VERSION 5.7 ;
  NOWIREEXTENSIONATPIN ON ;
  DIVIDERCHAR "/" ;
  BUSBITCHARS "[]" ;
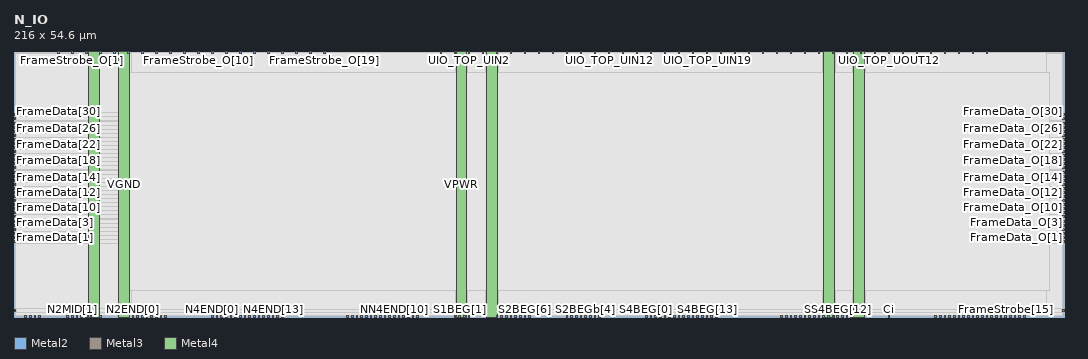
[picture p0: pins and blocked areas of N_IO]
MACRO N_IO
  CLASS BLOCK ;
  FOREIGN N_IO ;
  ORIGIN 0.000 0.000 ;
  SIZE 216.000 BY 54.600 ;
  PIN Ci
    DIRECTION INPUT ;
    USE SIGNAL ;
    PORT
      LAYER Metal2 ;
        RECT 179.800 0.000 180.200 0.400 ;
    END
  END Ci
  PIN FrameData[0]
    DIRECTION INPUT ;
    USE SIGNAL ;
    ANTENNAGATEAREA 0.180700 ;
    ANTENNADIFFAREA 2.015400 ;
    PORT
      LAYER Metal3 ;
        RECT 0.000 15.340 0.400 15.740 ;
    END
  END FrameData[0]
  PIN FrameData[10]
    DIRECTION INPUT ;
    USE SIGNAL ;
    ANTENNAGATEAREA 0.180700 ;
    ANTENNADIFFAREA 2.015400 ;
    PORT
      LAYER Metal3 ;
        RECT 0.000 23.740 0.400 24.140 ;
    END
  END FrameData[10]
  PIN FrameData[11]
    DIRECTION INPUT ;
    USE SIGNAL ;
    ANTENNAGATEAREA 0.180700 ;
    ANTENNADIFFAREA 2.015400 ;
    PORT
      LAYER Metal3 ;
        RECT 0.000 24.580 0.400 24.980 ;
    END
  END FrameData[11]
  PIN FrameData[12]
    DIRECTION INPUT ;
    USE SIGNAL ;
    ANTENNAGATEAREA 0.180700 ;
    ANTENNADIFFAREA 2.015400 ;
    PORT
      LAYER Metal3 ;
        RECT 0.000 25.420 0.400 25.820 ;
    END
  END FrameData[12]
  PIN FrameData[13]
    DIRECTION INPUT ;
    USE SIGNAL ;
    ANTENNAGATEAREA 0.180700 ;
    ANTENNADIFFAREA 2.015400 ;
    PORT
      LAYER Metal3 ;
        RECT 0.000 26.260 0.400 26.660 ;
    END
  END FrameData[13]
  PIN FrameData[14]
    DIRECTION INPUT ;
    USE SIGNAL ;
    ANTENNAGATEAREA 0.180700 ;
    ANTENNADIFFAREA 2.015400 ;
    PORT
      LAYER Metal3 ;
        RECT 0.000 27.100 0.400 27.500 ;
    END
  END FrameData[14]
  PIN FrameData[15]
    DIRECTION INPUT ;
    USE SIGNAL ;
    ANTENNAGATEAREA 0.180700 ;
    ANTENNADIFFAREA 2.015400 ;
    PORT
      LAYER Metal3 ;
        RECT 0.000 27.940 0.400 28.340 ;
    END
  END FrameData[15]
  PIN FrameData[16]
    DIRECTION INPUT ;
    USE SIGNAL ;
    ANTENNAGATEAREA 0.180700 ;
    ANTENNADIFFAREA 2.015400 ;
    PORT
      LAYER Metal3 ;
        RECT 0.000 28.780 0.400 29.180 ;
    END
  END FrameData[16]
  PIN FrameData[17]
    DIRECTION INPUT ;
    USE SIGNAL ;
    ANTENNAGATEAREA 0.180700 ;
    ANTENNADIFFAREA 2.015400 ;
    PORT
      LAYER Metal3 ;
        RECT 0.000 29.620 0.400 30.020 ;
    END
  END FrameData[17]
  PIN FrameData[18]
    DIRECTION INPUT ;
    USE SIGNAL ;
    ANTENNAGATEAREA 0.180700 ;
    ANTENNADIFFAREA 2.015400 ;
    PORT
      LAYER Metal3 ;
        RECT 0.000 30.460 0.400 30.860 ;
    END
  END FrameData[18]
  PIN FrameData[19]
    DIRECTION INPUT ;
    USE SIGNAL ;
    ANTENNAGATEAREA 0.180700 ;
    ANTENNADIFFAREA 2.015400 ;
    PORT
      LAYER Metal3 ;
        RECT 0.000 31.300 0.400 31.700 ;
    END
  END FrameData[19]
  PIN FrameData[1]
    DIRECTION INPUT ;
    USE SIGNAL ;
    ANTENNAGATEAREA 0.180700 ;
    ANTENNADIFFAREA 2.015400 ;
    PORT
      LAYER Metal3 ;
        RECT 0.000 16.180 0.400 16.580 ;
    END
  END FrameData[1]
  PIN FrameData[20]
    DIRECTION INPUT ;
    USE SIGNAL ;
    ANTENNAGATEAREA 0.180700 ;
    ANTENNADIFFAREA 2.015400 ;
    PORT
      LAYER Metal3 ;
        RECT 0.000 32.140 0.400 32.540 ;
    END
  END FrameData[20]
  PIN FrameData[21]
    DIRECTION INPUT ;
    USE SIGNAL ;
    ANTENNAGATEAREA 0.180700 ;
    ANTENNADIFFAREA 2.015400 ;
    PORT
      LAYER Metal3 ;
        RECT 0.000 32.980 0.400 33.380 ;
    END
  END FrameData[21]
  PIN FrameData[22]
    DIRECTION INPUT ;
    USE SIGNAL ;
    ANTENNAGATEAREA 0.180700 ;
    ANTENNADIFFAREA 2.015400 ;
    PORT
      LAYER Metal3 ;
        RECT 0.000 33.820 0.400 34.220 ;
    END
  END FrameData[22]
  PIN FrameData[23]
    DIRECTION INPUT ;
    USE SIGNAL ;
    ANTENNAGATEAREA 0.180700 ;
    ANTENNADIFFAREA 2.015400 ;
    PORT
      LAYER Metal3 ;
        RECT 0.000 34.660 0.400 35.060 ;
    END
  END FrameData[23]
  PIN FrameData[24]
    DIRECTION INPUT ;
    USE SIGNAL ;
    ANTENNAGATEAREA 0.180700 ;
    ANTENNADIFFAREA 2.015400 ;
    PORT
      LAYER Metal3 ;
        RECT 0.000 35.500 0.400 35.900 ;
    END
  END FrameData[24]
  PIN FrameData[25]
    DIRECTION INPUT ;
    USE SIGNAL ;
    ANTENNAGATEAREA 0.180700 ;
    ANTENNADIFFAREA 2.015400 ;
    PORT
      LAYER Metal3 ;
        RECT 0.000 36.340 0.400 36.740 ;
    END
  END FrameData[25]
  PIN FrameData[26]
    DIRECTION INPUT ;
    USE SIGNAL ;
    ANTENNAGATEAREA 0.180700 ;
    ANTENNADIFFAREA 2.015400 ;
    PORT
      LAYER Metal3 ;
        RECT 0.000 37.180 0.400 37.580 ;
    END
  END FrameData[26]
  PIN FrameData[27]
    DIRECTION INPUT ;
    USE SIGNAL ;
    ANTENNAGATEAREA 0.180700 ;
    ANTENNADIFFAREA 2.015400 ;
    PORT
      LAYER Metal3 ;
        RECT 0.000 38.020 0.400 38.420 ;
    END
  END FrameData[27]
  PIN FrameData[28]
    DIRECTION INPUT ;
    USE SIGNAL ;
    ANTENNAGATEAREA 0.180700 ;
    ANTENNADIFFAREA 2.015400 ;
    PORT
      LAYER Metal3 ;
        RECT 0.000 38.860 0.400 39.260 ;
    END
  END FrameData[28]
  PIN FrameData[29]
    DIRECTION INPUT ;
    USE SIGNAL ;
    ANTENNAGATEAREA 0.180700 ;
    ANTENNADIFFAREA 2.015400 ;
    PORT
      LAYER Metal3 ;
        RECT 0.000 39.700 0.400 40.100 ;
    END
  END FrameData[29]
  PIN FrameData[2]
    DIRECTION INPUT ;
    USE SIGNAL ;
    ANTENNAGATEAREA 0.180700 ;
    ANTENNADIFFAREA 2.015400 ;
    PORT
      LAYER Metal3 ;
        RECT 0.000 17.020 0.400 17.420 ;
    END
  END FrameData[2]
  PIN FrameData[30]
    DIRECTION INPUT ;
    USE SIGNAL ;
    ANTENNAGATEAREA 0.180700 ;
    ANTENNADIFFAREA 2.015400 ;
    PORT
      LAYER Metal3 ;
        RECT 0.000 40.540 0.400 40.940 ;
    END
  END FrameData[30]
  PIN FrameData[31]
    DIRECTION INPUT ;
    USE SIGNAL ;
    ANTENNAGATEAREA 0.180700 ;
    ANTENNADIFFAREA 2.015400 ;
    PORT
      LAYER Metal3 ;
        RECT 0.000 41.380 0.400 41.780 ;
    END
  END FrameData[31]
  PIN FrameData[3]
    DIRECTION INPUT ;
    USE SIGNAL ;
    ANTENNAGATEAREA 0.180700 ;
    ANTENNADIFFAREA 2.015400 ;
    PORT
      LAYER Metal3 ;
        RECT 0.000 17.860 0.400 18.260 ;
    END
  END FrameData[3]
  PIN FrameData[4]
    DIRECTION INPUT ;
    USE SIGNAL ;
    ANTENNAGATEAREA 0.180700 ;
    ANTENNADIFFAREA 2.015400 ;
    PORT
      LAYER Metal3 ;
        RECT 0.000 18.700 0.400 19.100 ;
    END
  END FrameData[4]
  PIN FrameData[5]
    DIRECTION INPUT ;
    USE SIGNAL ;
    ANTENNAGATEAREA 0.180700 ;
    ANTENNADIFFAREA 2.015400 ;
    PORT
      LAYER Metal3 ;
        RECT 0.000 19.540 0.400 19.940 ;
    END
  END FrameData[5]
  PIN FrameData[6]
    DIRECTION INPUT ;
    USE SIGNAL ;
    ANTENNAGATEAREA 0.180700 ;
    ANTENNADIFFAREA 2.015400 ;
    PORT
      LAYER Metal3 ;
        RECT 0.000 20.380 0.400 20.780 ;
    END
  END FrameData[6]
  PIN FrameData[7]
    DIRECTION INPUT ;
    USE SIGNAL ;
    ANTENNAGATEAREA 0.180700 ;
    ANTENNADIFFAREA 2.015400 ;
    PORT
      LAYER Metal3 ;
        RECT 0.000 21.220 0.400 21.620 ;
    END
  END FrameData[7]
  PIN FrameData[8]
    DIRECTION INPUT ;
    USE SIGNAL ;
    ANTENNAGATEAREA 0.180700 ;
    ANTENNADIFFAREA 2.015400 ;
    PORT
      LAYER Metal3 ;
        RECT 0.000 22.060 0.400 22.460 ;
    END
  END FrameData[8]
  PIN FrameData[9]
    DIRECTION INPUT ;
    USE SIGNAL ;
    ANTENNAGATEAREA 0.180700 ;
    ANTENNADIFFAREA 2.015400 ;
    PORT
      LAYER Metal3 ;
        RECT 0.000 22.900 0.400 23.300 ;
    END
  END FrameData[9]
  PIN FrameData_O[0]
    DIRECTION OUTPUT ;
    USE SIGNAL ;
    ANTENNADIFFAREA 2.724000 ;
    PORT
      LAYER Metal3 ;
        RECT 215.600 15.340 216.000 15.740 ;
    END
  END FrameData_O[0]
  PIN FrameData_O[10]
    DIRECTION OUTPUT ;
    USE SIGNAL ;
    ANTENNADIFFAREA 2.724000 ;
    PORT
      LAYER Metal3 ;
        RECT 215.600 23.740 216.000 24.140 ;
    END
  END FrameData_O[10]
  PIN FrameData_O[11]
    DIRECTION OUTPUT ;
    USE SIGNAL ;
    ANTENNADIFFAREA 2.724000 ;
    PORT
      LAYER Metal3 ;
        RECT 215.600 24.580 216.000 24.980 ;
    END
  END FrameData_O[11]
  PIN FrameData_O[12]
    DIRECTION OUTPUT ;
    USE SIGNAL ;
    ANTENNADIFFAREA 2.724000 ;
    PORT
      LAYER Metal3 ;
        RECT 215.600 25.420 216.000 25.820 ;
    END
  END FrameData_O[12]
  PIN FrameData_O[13]
    DIRECTION OUTPUT ;
    USE SIGNAL ;
    ANTENNADIFFAREA 2.724000 ;
    PORT
      LAYER Metal3 ;
        RECT 215.600 26.260 216.000 26.660 ;
    END
  END FrameData_O[13]
  PIN FrameData_O[14]
    DIRECTION OUTPUT ;
    USE SIGNAL ;
    ANTENNADIFFAREA 2.724000 ;
    PORT
      LAYER Metal3 ;
        RECT 215.600 27.100 216.000 27.500 ;
    END
  END FrameData_O[14]
  PIN FrameData_O[15]
    DIRECTION OUTPUT ;
    USE SIGNAL ;
    ANTENNADIFFAREA 2.724000 ;
    PORT
      LAYER Metal3 ;
        RECT 215.600 27.940 216.000 28.340 ;
    END
  END FrameData_O[15]
  PIN FrameData_O[16]
    DIRECTION OUTPUT ;
    USE SIGNAL ;
    ANTENNADIFFAREA 2.724000 ;
    PORT
      LAYER Metal3 ;
        RECT 215.600 28.780 216.000 29.180 ;
    END
  END FrameData_O[16]
  PIN FrameData_O[17]
    DIRECTION OUTPUT ;
    USE SIGNAL ;
    ANTENNADIFFAREA 2.724000 ;
    PORT
      LAYER Metal3 ;
        RECT 215.600 29.620 216.000 30.020 ;
    END
  END FrameData_O[17]
  PIN FrameData_O[18]
    DIRECTION OUTPUT ;
    USE SIGNAL ;
    ANTENNADIFFAREA 2.724000 ;
    PORT
      LAYER Metal3 ;
        RECT 215.600 30.460 216.000 30.860 ;
    END
  END FrameData_O[18]
  PIN FrameData_O[19]
    DIRECTION OUTPUT ;
    USE SIGNAL ;
    ANTENNADIFFAREA 2.724000 ;
    PORT
      LAYER Metal3 ;
        RECT 215.600 31.300 216.000 31.700 ;
    END
  END FrameData_O[19]
  PIN FrameData_O[1]
    DIRECTION OUTPUT ;
    USE SIGNAL ;
    ANTENNADIFFAREA 2.724000 ;
    PORT
      LAYER Metal3 ;
        RECT 215.600 16.180 216.000 16.580 ;
    END
  END FrameData_O[1]
  PIN FrameData_O[20]
    DIRECTION OUTPUT ;
    USE SIGNAL ;
    ANTENNADIFFAREA 2.724000 ;
    PORT
      LAYER Metal3 ;
        RECT 215.600 32.140 216.000 32.540 ;
    END
  END FrameData_O[20]
  PIN FrameData_O[21]
    DIRECTION OUTPUT ;
    USE SIGNAL ;
    ANTENNADIFFAREA 2.724000 ;
    PORT
      LAYER Metal3 ;
        RECT 215.600 32.980 216.000 33.380 ;
    END
  END FrameData_O[21]
  PIN FrameData_O[22]
    DIRECTION OUTPUT ;
    USE SIGNAL ;
    ANTENNADIFFAREA 2.724000 ;
    PORT
      LAYER Metal3 ;
        RECT 215.600 33.820 216.000 34.220 ;
    END
  END FrameData_O[22]
  PIN FrameData_O[23]
    DIRECTION OUTPUT ;
    USE SIGNAL ;
    ANTENNADIFFAREA 2.724000 ;
    PORT
      LAYER Metal3 ;
        RECT 215.600 34.660 216.000 35.060 ;
    END
  END FrameData_O[23]
  PIN FrameData_O[24]
    DIRECTION OUTPUT ;
    USE SIGNAL ;
    ANTENNADIFFAREA 2.724000 ;
    PORT
      LAYER Metal3 ;
        RECT 215.600 35.500 216.000 35.900 ;
    END
  END FrameData_O[24]
  PIN FrameData_O[25]
    DIRECTION OUTPUT ;
    USE SIGNAL ;
    ANTENNADIFFAREA 2.724000 ;
    PORT
      LAYER Metal3 ;
        RECT 215.600 36.340 216.000 36.740 ;
    END
  END FrameData_O[25]
  PIN FrameData_O[26]
    DIRECTION OUTPUT ;
    USE SIGNAL ;
    ANTENNADIFFAREA 2.724000 ;
    PORT
      LAYER Metal3 ;
        RECT 215.600 37.180 216.000 37.580 ;
    END
  END FrameData_O[26]
  PIN FrameData_O[27]
    DIRECTION OUTPUT ;
    USE SIGNAL ;
    ANTENNADIFFAREA 2.724000 ;
    PORT
      LAYER Metal3 ;
        RECT 215.600 38.020 216.000 38.420 ;
    END
  END FrameData_O[27]
  PIN FrameData_O[28]
    DIRECTION OUTPUT ;
    USE SIGNAL ;
    ANTENNADIFFAREA 2.724000 ;
    PORT
      LAYER Metal3 ;
        RECT 215.600 38.860 216.000 39.260 ;
    END
  END FrameData_O[28]
  PIN FrameData_O[29]
    DIRECTION OUTPUT ;
    USE SIGNAL ;
    ANTENNADIFFAREA 2.724000 ;
    PORT
      LAYER Metal3 ;
        RECT 215.600 39.700 216.000 40.100 ;
    END
  END FrameData_O[29]
  PIN FrameData_O[2]
    DIRECTION OUTPUT ;
    USE SIGNAL ;
    ANTENNADIFFAREA 2.724000 ;
    PORT
      LAYER Metal3 ;
        RECT 215.600 17.020 216.000 17.420 ;
    END
  END FrameData_O[2]
  PIN FrameData_O[30]
    DIRECTION OUTPUT ;
    USE SIGNAL ;
    ANTENNADIFFAREA 2.724000 ;
    PORT
      LAYER Metal3 ;
        RECT 215.600 40.540 216.000 40.940 ;
    END
  END FrameData_O[30]
  PIN FrameData_O[31]
    DIRECTION OUTPUT ;
    USE SIGNAL ;
    ANTENNADIFFAREA 2.724000 ;
    PORT
      LAYER Metal3 ;
        RECT 215.600 41.380 216.000 41.780 ;
    END
  END FrameData_O[31]
  PIN FrameData_O[3]
    DIRECTION OUTPUT ;
    USE SIGNAL ;
    ANTENNADIFFAREA 2.724000 ;
    PORT
      LAYER Metal3 ;
        RECT 215.600 17.860 216.000 18.260 ;
    END
  END FrameData_O[3]
  PIN FrameData_O[4]
    DIRECTION OUTPUT ;
    USE SIGNAL ;
    ANTENNADIFFAREA 2.724000 ;
    PORT
      LAYER Metal3 ;
        RECT 215.600 18.700 216.000 19.100 ;
    END
  END FrameData_O[4]
  PIN FrameData_O[5]
    DIRECTION OUTPUT ;
    USE SIGNAL ;
    ANTENNADIFFAREA 2.724000 ;
    PORT
      LAYER Metal3 ;
        RECT 215.600 19.540 216.000 19.940 ;
    END
  END FrameData_O[5]
  PIN FrameData_O[6]
    DIRECTION OUTPUT ;
    USE SIGNAL ;
    ANTENNADIFFAREA 2.724000 ;
    PORT
      LAYER Metal3 ;
        RECT 215.600 20.380 216.000 20.780 ;
    END
  END FrameData_O[6]
  PIN FrameData_O[7]
    DIRECTION OUTPUT ;
    USE SIGNAL ;
    ANTENNADIFFAREA 2.724000 ;
    PORT
      LAYER Metal3 ;
        RECT 215.600 21.220 216.000 21.620 ;
    END
  END FrameData_O[7]
  PIN FrameData_O[8]
    DIRECTION OUTPUT ;
    USE SIGNAL ;
    ANTENNADIFFAREA 2.724000 ;
    PORT
      LAYER Metal3 ;
        RECT 215.600 22.060 216.000 22.460 ;
    END
  END FrameData_O[8]
  PIN FrameData_O[9]
    DIRECTION OUTPUT ;
    USE SIGNAL ;
    ANTENNADIFFAREA 2.724000 ;
    PORT
      LAYER Metal3 ;
        RECT 215.600 22.900 216.000 23.300 ;
    END
  END FrameData_O[9]
  PIN FrameStrobe[0]
    DIRECTION INPUT ;
    USE SIGNAL ;
    ANTENNAGATEAREA 0.180700 ;
    ANTENNADIFFAREA 2.015400 ;
    PORT
      LAYER Metal2 ;
        RECT 189.400 0.000 189.800 0.400 ;
    END
  END FrameStrobe[0]
  PIN FrameStrobe[10]
    DIRECTION INPUT ;
    USE SIGNAL ;
    ANTENNAGATEAREA 0.180700 ;
    ANTENNADIFFAREA 2.015400 ;
    PORT
      LAYER Metal2 ;
        RECT 199.000 0.000 199.400 0.400 ;
    END
  END FrameStrobe[10]
  PIN FrameStrobe[11]
    DIRECTION INPUT ;
    USE SIGNAL ;
    ANTENNAGATEAREA 0.180700 ;
    ANTENNADIFFAREA 2.015400 ;
    PORT
      LAYER Metal2 ;
        RECT 199.960 0.000 200.360 0.400 ;
    END
  END FrameStrobe[11]
  PIN FrameStrobe[12]
    DIRECTION INPUT ;
    USE SIGNAL ;
    ANTENNAGATEAREA 0.180700 ;
    ANTENNADIFFAREA 2.015400 ;
    PORT
      LAYER Metal2 ;
        RECT 200.920 0.000 201.320 0.400 ;
    END
  END FrameStrobe[12]
  PIN FrameStrobe[13]
    DIRECTION INPUT ;
    USE SIGNAL ;
    ANTENNAGATEAREA 0.180700 ;
    ANTENNADIFFAREA 2.015400 ;
    PORT
      LAYER Metal2 ;
        RECT 201.880 0.000 202.280 0.400 ;
    END
  END FrameStrobe[13]
  PIN FrameStrobe[14]
    DIRECTION INPUT ;
    USE SIGNAL ;
    ANTENNAGATEAREA 0.180700 ;
    ANTENNADIFFAREA 2.015400 ;
    PORT
      LAYER Metal2 ;
        RECT 202.840 0.000 203.240 0.400 ;
    END
  END FrameStrobe[14]
  PIN FrameStrobe[15]
    DIRECTION INPUT ;
    USE SIGNAL ;
    ANTENNAGATEAREA 0.180700 ;
    ANTENNADIFFAREA 2.015400 ;
    PORT
      LAYER Metal2 ;
        RECT 203.800 0.000 204.200 0.400 ;
    END
  END FrameStrobe[15]
  PIN FrameStrobe[16]
    DIRECTION INPUT ;
    USE SIGNAL ;
    ANTENNAGATEAREA 0.180700 ;
    ANTENNADIFFAREA 2.015400 ;
    PORT
      LAYER Metal2 ;
        RECT 204.760 0.000 205.160 0.400 ;
    END
  END FrameStrobe[16]
  PIN FrameStrobe[17]
    DIRECTION INPUT ;
    USE SIGNAL ;
    ANTENNAGATEAREA 0.180700 ;
    ANTENNADIFFAREA 2.015400 ;
    PORT
      LAYER Metal2 ;
        RECT 205.720 0.000 206.120 0.400 ;
    END
  END FrameStrobe[17]
  PIN FrameStrobe[18]
    DIRECTION INPUT ;
    USE SIGNAL ;
    ANTENNAGATEAREA 0.180700 ;
    ANTENNADIFFAREA 2.015400 ;
    PORT
      LAYER Metal2 ;
        RECT 206.680 0.000 207.080 0.400 ;
    END
  END FrameStrobe[18]
  PIN FrameStrobe[19]
    DIRECTION INPUT ;
    USE SIGNAL ;
    ANTENNAGATEAREA 0.180700 ;
    ANTENNADIFFAREA 2.015400 ;
    PORT
      LAYER Metal2 ;
        RECT 207.640 0.000 208.040 0.400 ;
    END
  END FrameStrobe[19]
  PIN FrameStrobe[1]
    DIRECTION INPUT ;
    USE SIGNAL ;
    ANTENNAGATEAREA 0.180700 ;
    ANTENNADIFFAREA 2.015400 ;
    PORT
      LAYER Metal2 ;
        RECT 190.360 0.000 190.760 0.400 ;
    END
  END FrameStrobe[1]
  PIN FrameStrobe[2]
    DIRECTION INPUT ;
    USE SIGNAL ;
    ANTENNAGATEAREA 0.180700 ;
    ANTENNADIFFAREA 2.015400 ;
    PORT
      LAYER Metal2 ;
        RECT 191.320 0.000 191.720 0.400 ;
    END
  END FrameStrobe[2]
  PIN FrameStrobe[3]
    DIRECTION INPUT ;
    USE SIGNAL ;
    ANTENNAGATEAREA 0.180700 ;
    ANTENNADIFFAREA 2.015400 ;
    PORT
      LAYER Metal2 ;
        RECT 192.280 0.000 192.680 0.400 ;
    END
  END FrameStrobe[3]
  PIN FrameStrobe[4]
    DIRECTION INPUT ;
    USE SIGNAL ;
    ANTENNAGATEAREA 0.180700 ;
    ANTENNADIFFAREA 2.015400 ;
    PORT
      LAYER Metal2 ;
        RECT 193.240 0.000 193.640 0.400 ;
    END
  END FrameStrobe[4]
  PIN FrameStrobe[5]
    DIRECTION INPUT ;
    USE SIGNAL ;
    ANTENNAGATEAREA 0.180700 ;
    ANTENNADIFFAREA 2.015400 ;
    PORT
      LAYER Metal2 ;
        RECT 194.200 0.000 194.600 0.400 ;
    END
  END FrameStrobe[5]
  PIN FrameStrobe[6]
    DIRECTION INPUT ;
    USE SIGNAL ;
    ANTENNAGATEAREA 0.180700 ;
    ANTENNADIFFAREA 2.015400 ;
    PORT
      LAYER Metal2 ;
        RECT 195.160 0.000 195.560 0.400 ;
    END
  END FrameStrobe[6]
  PIN FrameStrobe[7]
    DIRECTION INPUT ;
    USE SIGNAL ;
    ANTENNAGATEAREA 0.180700 ;
    ANTENNADIFFAREA 2.015400 ;
    PORT
      LAYER Metal2 ;
        RECT 196.120 0.000 196.520 0.400 ;
    END
  END FrameStrobe[7]
  PIN FrameStrobe[8]
    DIRECTION INPUT ;
    USE SIGNAL ;
    ANTENNAGATEAREA 0.180700 ;
    ANTENNADIFFAREA 2.015400 ;
    PORT
      LAYER Metal2 ;
        RECT 197.080 0.000 197.480 0.400 ;
    END
  END FrameStrobe[8]
  PIN FrameStrobe[9]
    DIRECTION INPUT ;
    USE SIGNAL ;
    ANTENNAGATEAREA 0.180700 ;
    ANTENNADIFFAREA 2.015400 ;
    PORT
      LAYER Metal2 ;
        RECT 198.040 0.000 198.440 0.400 ;
    END
  END FrameStrobe[9]
  PIN FrameStrobe_O[0]
    DIRECTION OUTPUT ;
    USE SIGNAL ;
    ANTENNADIFFAREA 2.724000 ;
    PORT
      LAYER Metal2 ;
        RECT 8.920 54.200 9.320 54.600 ;
    END
  END FrameStrobe_O[0]
  PIN FrameStrobe_O[10]
    DIRECTION OUTPUT ;
    USE SIGNAL ;
    ANTENNADIFFAREA 2.724000 ;
    PORT
      LAYER Metal2 ;
        RECT 37.720 54.200 38.120 54.600 ;
    END
  END FrameStrobe_O[10]
  PIN FrameStrobe_O[11]
    DIRECTION OUTPUT ;
    USE SIGNAL ;
    ANTENNADIFFAREA 2.724000 ;
    PORT
      LAYER Metal2 ;
        RECT 40.600 54.200 41.000 54.600 ;
    END
  END FrameStrobe_O[11]
  PIN FrameStrobe_O[12]
    DIRECTION OUTPUT ;
    USE SIGNAL ;
    ANTENNADIFFAREA 2.724000 ;
    PORT
      LAYER Metal2 ;
        RECT 43.480 54.200 43.880 54.600 ;
    END
  END FrameStrobe_O[12]
  PIN FrameStrobe_O[13]
    DIRECTION OUTPUT ;
    USE SIGNAL ;
    ANTENNADIFFAREA 2.724000 ;
    PORT
      LAYER Metal2 ;
        RECT 46.360 54.200 46.760 54.600 ;
    END
  END FrameStrobe_O[13]
  PIN FrameStrobe_O[14]
    DIRECTION OUTPUT ;
    USE SIGNAL ;
    ANTENNADIFFAREA 2.724000 ;
    PORT
      LAYER Metal2 ;
        RECT 49.240 54.200 49.640 54.600 ;
    END
  END FrameStrobe_O[14]
  PIN FrameStrobe_O[15]
    DIRECTION OUTPUT ;
    USE SIGNAL ;
    ANTENNADIFFAREA 2.724000 ;
    PORT
      LAYER Metal2 ;
        RECT 52.120 54.200 52.520 54.600 ;
    END
  END FrameStrobe_O[15]
  PIN FrameStrobe_O[16]
    DIRECTION OUTPUT ;
    USE SIGNAL ;
    ANTENNADIFFAREA 2.724000 ;
    PORT
      LAYER Metal2 ;
        RECT 55.000 54.200 55.400 54.600 ;
    END
  END FrameStrobe_O[16]
  PIN FrameStrobe_O[17]
    DIRECTION OUTPUT ;
    USE SIGNAL ;
    ANTENNADIFFAREA 2.724000 ;
    PORT
      LAYER Metal2 ;
        RECT 57.880 54.200 58.280 54.600 ;
    END
  END FrameStrobe_O[17]
  PIN FrameStrobe_O[18]
    DIRECTION OUTPUT ;
    USE SIGNAL ;
    ANTENNADIFFAREA 2.724000 ;
    PORT
      LAYER Metal2 ;
        RECT 60.760 54.200 61.160 54.600 ;
    END
  END FrameStrobe_O[18]
  PIN FrameStrobe_O[19]
    DIRECTION OUTPUT ;
    USE SIGNAL ;
    ANTENNADIFFAREA 2.724000 ;
    PORT
      LAYER Metal2 ;
        RECT 63.640 54.200 64.040 54.600 ;
    END
  END FrameStrobe_O[19]
  PIN FrameStrobe_O[1]
    DIRECTION OUTPUT ;
    USE SIGNAL ;
    ANTENNADIFFAREA 2.724000 ;
    PORT
      LAYER Metal2 ;
        RECT 11.800 54.200 12.200 54.600 ;
    END
  END FrameStrobe_O[1]
  PIN FrameStrobe_O[2]
    DIRECTION OUTPUT ;
    USE SIGNAL ;
    ANTENNADIFFAREA 2.724000 ;
    PORT
      LAYER Metal2 ;
        RECT 14.680 54.200 15.080 54.600 ;
    END
  END FrameStrobe_O[2]
  PIN FrameStrobe_O[3]
    DIRECTION OUTPUT ;
    USE SIGNAL ;
    ANTENNADIFFAREA 2.724000 ;
    PORT
      LAYER Metal2 ;
        RECT 17.560 54.200 17.960 54.600 ;
    END
  END FrameStrobe_O[3]
  PIN FrameStrobe_O[4]
    DIRECTION OUTPUT ;
    USE SIGNAL ;
    ANTENNADIFFAREA 2.724000 ;
    PORT
      LAYER Metal2 ;
        RECT 20.440 54.200 20.840 54.600 ;
    END
  END FrameStrobe_O[4]
  PIN FrameStrobe_O[5]
    DIRECTION OUTPUT ;
    USE SIGNAL ;
    ANTENNADIFFAREA 2.724000 ;
    PORT
      LAYER Metal2 ;
        RECT 23.320 54.200 23.720 54.600 ;
    END
  END FrameStrobe_O[5]
  PIN FrameStrobe_O[6]
    DIRECTION OUTPUT ;
    USE SIGNAL ;
    ANTENNADIFFAREA 2.724000 ;
    PORT
      LAYER Metal2 ;
        RECT 26.200 54.200 26.600 54.600 ;
    END
  END FrameStrobe_O[6]
  PIN FrameStrobe_O[7]
    DIRECTION OUTPUT ;
    USE SIGNAL ;
    ANTENNADIFFAREA 2.724000 ;
    PORT
      LAYER Metal2 ;
        RECT 29.080 54.200 29.480 54.600 ;
    END
  END FrameStrobe_O[7]
  PIN FrameStrobe_O[8]
    DIRECTION OUTPUT ;
    USE SIGNAL ;
    ANTENNADIFFAREA 2.724000 ;
    PORT
      LAYER Metal2 ;
        RECT 31.960 54.200 32.360 54.600 ;
    END
  END FrameStrobe_O[8]
  PIN FrameStrobe_O[9]
    DIRECTION OUTPUT ;
    USE SIGNAL ;
    ANTENNADIFFAREA 2.724000 ;
    PORT
      LAYER Metal2 ;
        RECT 34.840 54.200 35.240 54.600 ;
    END
  END FrameStrobe_O[9]
  PIN N1END[0]
    DIRECTION INPUT ;
    USE SIGNAL ;
    ANTENNAGATEAREA 0.180700 ;
    ANTENNADIFFAREA 2.015400 ;
    PORT
      LAYER Metal2 ;
        RECT 2.200 0.000 2.600 0.400 ;
    END
  END N1END[0]
  PIN N1END[1]
    DIRECTION INPUT ;
    USE SIGNAL ;
    ANTENNAGATEAREA 0.180700 ;
    ANTENNADIFFAREA 2.015400 ;
    PORT
      LAYER Metal2 ;
        RECT 3.160 0.000 3.560 0.400 ;
    END
  END N1END[1]
  PIN N1END[2]
    DIRECTION INPUT ;
    USE SIGNAL ;
    ANTENNAGATEAREA 0.180700 ;
    ANTENNADIFFAREA 2.015400 ;
    PORT
      LAYER Metal2 ;
        RECT 4.120 0.000 4.520 0.400 ;
    END
  END N1END[2]
  PIN N1END[3]
    DIRECTION INPUT ;
    USE SIGNAL ;
    ANTENNAGATEAREA 0.180700 ;
    ANTENNADIFFAREA 2.015400 ;
    PORT
      LAYER Metal2 ;
        RECT 5.080 0.000 5.480 0.400 ;
    END
  END N1END[3]
  PIN N2END[0]
    DIRECTION INPUT ;
    USE SIGNAL ;
    ANTENNAGATEAREA 0.180700 ;
    ANTENNADIFFAREA 2.015400 ;
    PORT
      LAYER Metal2 ;
        RECT 24.280 0.000 24.680 0.400 ;
    END
  END N2END[0]
  PIN N2END[1]
    DIRECTION INPUT ;
    USE SIGNAL ;
    ANTENNAGATEAREA 0.180700 ;
    ANTENNADIFFAREA 2.015400 ;
    PORT
      LAYER Metal2 ;
        RECT 25.240 0.000 25.640 0.400 ;
    END
  END N2END[1]
  PIN N2END[2]
    DIRECTION INPUT ;
    USE SIGNAL ;
    ANTENNAGATEAREA 0.180700 ;
    ANTENNADIFFAREA 2.015400 ;
    PORT
      LAYER Metal2 ;
        RECT 26.200 0.000 26.600 0.400 ;
    END
  END N2END[2]
  PIN N2END[3]
    DIRECTION INPUT ;
    USE SIGNAL ;
    ANTENNAGATEAREA 0.180700 ;
    ANTENNADIFFAREA 2.015400 ;
    PORT
      LAYER Metal2 ;
        RECT 27.160 0.000 27.560 0.400 ;
    END
  END N2END[3]
  PIN N2END[4]
    DIRECTION INPUT ;
    USE SIGNAL ;
    ANTENNAGATEAREA 0.180700 ;
    ANTENNADIFFAREA 2.015400 ;
    PORT
      LAYER Metal2 ;
        RECT 28.120 0.000 28.520 0.400 ;
    END
  END N2END[4]
  PIN N2END[5]
    DIRECTION INPUT ;
    USE SIGNAL ;
    ANTENNAGATEAREA 0.180700 ;
    ANTENNADIFFAREA 2.015400 ;
    PORT
      LAYER Metal2 ;
        RECT 29.080 0.000 29.480 0.400 ;
    END
  END N2END[5]
  PIN N2END[6]
    DIRECTION INPUT ;
    USE SIGNAL ;
    ANTENNAGATEAREA 0.180700 ;
    ANTENNADIFFAREA 2.015400 ;
    PORT
      LAYER Metal2 ;
        RECT 30.040 0.000 30.440 0.400 ;
    END
  END N2END[6]
  PIN N2END[7]
    DIRECTION INPUT ;
    USE SIGNAL ;
    ANTENNAGATEAREA 0.180700 ;
    ANTENNADIFFAREA 2.015400 ;
    PORT
      LAYER Metal2 ;
        RECT 31.000 0.000 31.400 0.400 ;
    END
  END N2END[7]
  PIN N2MID[0]
    DIRECTION INPUT ;
    USE SIGNAL ;
    ANTENNAGATEAREA 0.180700 ;
    ANTENNADIFFAREA 2.015400 ;
    PORT
      LAYER Metal2 ;
        RECT 10.840 0.000 11.240 0.400 ;
    END
  END N2MID[0]
  PIN N2MID[1]
    DIRECTION INPUT ;
    USE SIGNAL ;
    ANTENNAGATEAREA 0.180700 ;
    ANTENNADIFFAREA 2.015400 ;
    PORT
      LAYER Metal2 ;
        RECT 11.800 0.000 12.200 0.400 ;
    END
  END N2MID[1]
  PIN N2MID[2]
    DIRECTION INPUT ;
    USE SIGNAL ;
    ANTENNAGATEAREA 0.180700 ;
    ANTENNADIFFAREA 2.015400 ;
    PORT
      LAYER Metal2 ;
        RECT 12.760 0.000 13.160 0.400 ;
    END
  END N2MID[2]
  PIN N2MID[3]
    DIRECTION INPUT ;
    USE SIGNAL ;
    ANTENNAGATEAREA 0.180700 ;
    ANTENNADIFFAREA 2.015400 ;
    PORT
      LAYER Metal2 ;
        RECT 13.720 0.000 14.120 0.400 ;
    END
  END N2MID[3]
  PIN N2MID[4]
    DIRECTION INPUT ;
    USE SIGNAL ;
    ANTENNAGATEAREA 0.180700 ;
    ANTENNADIFFAREA 2.015400 ;
    PORT
      LAYER Metal2 ;
        RECT 14.680 0.000 15.080 0.400 ;
    END
  END N2MID[4]
  PIN N2MID[5]
    DIRECTION INPUT ;
    USE SIGNAL ;
    ANTENNAGATEAREA 0.180700 ;
    ANTENNADIFFAREA 2.015400 ;
    PORT
      LAYER Metal2 ;
        RECT 15.640 0.000 16.040 0.400 ;
    END
  END N2MID[5]
  PIN N2MID[6]
    DIRECTION INPUT ;
    USE SIGNAL ;
    ANTENNAGATEAREA 0.180700 ;
    ANTENNADIFFAREA 2.015400 ;
    PORT
      LAYER Metal2 ;
        RECT 16.600 0.000 17.000 0.400 ;
    END
  END N2MID[6]
  PIN N2MID[7]
    DIRECTION INPUT ;
    USE SIGNAL ;
    ANTENNAGATEAREA 0.180700 ;
    ANTENNADIFFAREA 2.015400 ;
    PORT
      LAYER Metal2 ;
        RECT 17.560 0.000 17.960 0.400 ;
    END
  END N2MID[7]
  PIN N4END[0]
    DIRECTION INPUT ;
    USE SIGNAL ;
    ANTENNAGATEAREA 0.180700 ;
    ANTENNADIFFAREA 2.015400 ;
    PORT
      LAYER Metal2 ;
        RECT 40.600 0.000 41.000 0.400 ;
    END
  END N4END[0]
  PIN N4END[10]
    DIRECTION INPUT ;
    USE SIGNAL ;
    ANTENNAGATEAREA 0.180700 ;
    ANTENNADIFFAREA 2.015400 ;
    PORT
      LAYER Metal2 ;
        RECT 50.200 0.000 50.600 0.400 ;
    END
  END N4END[10]
  PIN N4END[11]
    DIRECTION INPUT ;
    USE SIGNAL ;
    ANTENNAGATEAREA 0.180700 ;
    ANTENNADIFFAREA 2.015400 ;
    PORT
      LAYER Metal2 ;
        RECT 51.160 0.000 51.560 0.400 ;
    END
  END N4END[11]
  PIN N4END[12]
    DIRECTION INPUT ;
    USE SIGNAL ;
    PORT
      LAYER Metal2 ;
        RECT 52.120 0.000 52.520 0.400 ;
    END
  END N4END[12]
  PIN N4END[13]
    DIRECTION INPUT ;
    USE SIGNAL ;
    PORT
      LAYER Metal2 ;
        RECT 53.080 0.000 53.480 0.400 ;
    END
  END N4END[13]
  PIN N4END[14]
    DIRECTION INPUT ;
    USE SIGNAL ;
    PORT
      LAYER Metal2 ;
        RECT 54.040 0.000 54.440 0.400 ;
    END
  END N4END[14]
  PIN N4END[15]
    DIRECTION INPUT ;
    USE SIGNAL ;
    PORT
      LAYER Metal2 ;
        RECT 55.000 0.000 55.400 0.400 ;
    END
  END N4END[15]
  PIN N4END[1]
    DIRECTION INPUT ;
    USE SIGNAL ;
    ANTENNAGATEAREA 0.180700 ;
    ANTENNADIFFAREA 2.015400 ;
    PORT
      LAYER Metal2 ;
        RECT 41.560 0.000 41.960 0.400 ;
    END
  END N4END[1]
  PIN N4END[2]
    DIRECTION INPUT ;
    USE SIGNAL ;
    ANTENNAGATEAREA 0.180700 ;
    ANTENNADIFFAREA 2.015400 ;
    PORT
      LAYER Metal2 ;
        RECT 42.520 0.000 42.920 0.400 ;
    END
  END N4END[2]
  PIN N4END[3]
    DIRECTION INPUT ;
    USE SIGNAL ;
    ANTENNAGATEAREA 0.180700 ;
    ANTENNADIFFAREA 2.015400 ;
    PORT
      LAYER Metal2 ;
        RECT 43.480 0.000 43.880 0.400 ;
    END
  END N4END[3]
  PIN N4END[4]
    DIRECTION INPUT ;
    USE SIGNAL ;
    ANTENNAGATEAREA 0.180700 ;
    ANTENNADIFFAREA 2.015400 ;
    PORT
      LAYER Metal2 ;
        RECT 44.440 0.000 44.840 0.400 ;
    END
  END N4END[4]
  PIN N4END[5]
    DIRECTION INPUT ;
    USE SIGNAL ;
    ANTENNAGATEAREA 0.180700 ;
    ANTENNADIFFAREA 2.015400 ;
    PORT
      LAYER Metal2 ;
        RECT 45.400 0.000 45.800 0.400 ;
    END
  END N4END[5]
  PIN N4END[6]
    DIRECTION INPUT ;
    USE SIGNAL ;
    ANTENNAGATEAREA 0.180700 ;
    ANTENNADIFFAREA 2.015400 ;
    PORT
      LAYER Metal2 ;
        RECT 46.360 0.000 46.760 0.400 ;
    END
  END N4END[6]
  PIN N4END[7]
    DIRECTION INPUT ;
    USE SIGNAL ;
    ANTENNAGATEAREA 0.180700 ;
    ANTENNADIFFAREA 2.015400 ;
    PORT
      LAYER Metal2 ;
        RECT 47.320 0.000 47.720 0.400 ;
    END
  END N4END[7]
  PIN N4END[8]
    DIRECTION INPUT ;
    USE SIGNAL ;
    ANTENNAGATEAREA 0.180700 ;
    ANTENNADIFFAREA 2.015400 ;
    PORT
      LAYER Metal2 ;
        RECT 48.280 0.000 48.680 0.400 ;
    END
  END N4END[8]
  PIN N4END[9]
    DIRECTION INPUT ;
    USE SIGNAL ;
    ANTENNAGATEAREA 0.180700 ;
    ANTENNADIFFAREA 2.015400 ;
    PORT
      LAYER Metal2 ;
        RECT 49.240 0.000 49.640 0.400 ;
    END
  END N4END[9]
  PIN NN4END[0]
    DIRECTION INPUT ;
    USE SIGNAL ;
    ANTENNAGATEAREA 0.361400 ;
    ANTENNADIFFAREA 4.030800 ;
    PORT
      LAYER Metal2 ;
        RECT 68.440 0.000 68.840 0.400 ;
    END
  END NN4END[0]
  PIN NN4END[10]
    DIRECTION INPUT ;
    USE SIGNAL ;
    ANTENNAGATEAREA 0.180700 ;
    ANTENNADIFFAREA 2.015400 ;
    PORT
      LAYER Metal2 ;
        RECT 78.040 0.000 78.440 0.400 ;
    END
  END NN4END[10]
  PIN NN4END[11]
    DIRECTION INPUT ;
    USE SIGNAL ;
    ANTENNAGATEAREA 0.180700 ;
    ANTENNADIFFAREA 2.015400 ;
    PORT
      LAYER Metal2 ;
        RECT 79.000 0.000 79.400 0.400 ;
    END
  END NN4END[11]
  PIN NN4END[12]
    DIRECTION INPUT ;
    USE SIGNAL ;
    ANTENNAGATEAREA 0.180700 ;
    ANTENNADIFFAREA 2.015400 ;
    PORT
      LAYER Metal2 ;
        RECT 79.960 0.000 80.360 0.400 ;
    END
  END NN4END[12]
  PIN NN4END[13]
    DIRECTION INPUT ;
    USE SIGNAL ;
    ANTENNAGATEAREA 0.180700 ;
    ANTENNADIFFAREA 2.015400 ;
    PORT
      LAYER Metal2 ;
        RECT 80.920 0.000 81.320 0.400 ;
    END
  END NN4END[13]
  PIN NN4END[14]
    DIRECTION INPUT ;
    USE SIGNAL ;
    ANTENNAGATEAREA 0.180700 ;
    ANTENNADIFFAREA 2.015400 ;
    PORT
      LAYER Metal2 ;
        RECT 81.880 0.000 82.280 0.400 ;
    END
  END NN4END[14]
  PIN NN4END[15]
    DIRECTION INPUT ;
    USE SIGNAL ;
    ANTENNAGATEAREA 0.180700 ;
    ANTENNADIFFAREA 2.015400 ;
    PORT
      LAYER Metal2 ;
        RECT 82.840 0.000 83.240 0.400 ;
    END
  END NN4END[15]
  PIN NN4END[1]
    DIRECTION INPUT ;
    USE SIGNAL ;
    ANTENNAGATEAREA 0.361400 ;
    ANTENNADIFFAREA 4.030800 ;
    PORT
      LAYER Metal2 ;
        RECT 69.400 0.000 69.800 0.400 ;
    END
  END NN4END[1]
  PIN NN4END[2]
    DIRECTION INPUT ;
    USE SIGNAL ;
    ANTENNAGATEAREA 0.361400 ;
    ANTENNADIFFAREA 4.030800 ;
    PORT
      LAYER Metal2 ;
        RECT 70.360 0.000 70.760 0.400 ;
    END
  END NN4END[2]
  PIN NN4END[3]
    DIRECTION INPUT ;
    USE SIGNAL ;
    ANTENNAGATEAREA 0.361400 ;
    ANTENNADIFFAREA 4.030800 ;
    PORT
      LAYER Metal2 ;
        RECT 71.320 0.000 71.720 0.400 ;
    END
  END NN4END[3]
  PIN NN4END[4]
    DIRECTION INPUT ;
    USE SIGNAL ;
    ANTENNAGATEAREA 0.180700 ;
    ANTENNADIFFAREA 2.015400 ;
    PORT
      LAYER Metal2 ;
        RECT 72.280 0.000 72.680 0.400 ;
    END
  END NN4END[4]
  PIN NN4END[5]
    DIRECTION INPUT ;
    USE SIGNAL ;
    ANTENNAGATEAREA 0.180700 ;
    ANTENNADIFFAREA 2.015400 ;
    PORT
      LAYER Metal2 ;
        RECT 73.240 0.000 73.640 0.400 ;
    END
  END NN4END[5]
  PIN NN4END[6]
    DIRECTION INPUT ;
    USE SIGNAL ;
    ANTENNAGATEAREA 0.180700 ;
    ANTENNADIFFAREA 2.015400 ;
    PORT
      LAYER Metal2 ;
        RECT 74.200 0.000 74.600 0.400 ;
    END
  END NN4END[6]
  PIN NN4END[7]
    DIRECTION INPUT ;
    USE SIGNAL ;
    ANTENNAGATEAREA 0.180700 ;
    ANTENNADIFFAREA 2.015400 ;
    PORT
      LAYER Metal2 ;
        RECT 75.160 0.000 75.560 0.400 ;
    END
  END NN4END[7]
  PIN NN4END[8]
    DIRECTION INPUT ;
    USE SIGNAL ;
    ANTENNAGATEAREA 0.180700 ;
    ANTENNADIFFAREA 2.015400 ;
    PORT
      LAYER Metal2 ;
        RECT 76.120 0.000 76.520 0.400 ;
    END
  END NN4END[8]
  PIN NN4END[9]
    DIRECTION INPUT ;
    USE SIGNAL ;
    ANTENNAGATEAREA 0.180700 ;
    ANTENNADIFFAREA 2.015400 ;
    PORT
      LAYER Metal2 ;
        RECT 77.080 0.000 77.480 0.400 ;
    END
  END NN4END[9]
  PIN S1BEG[0]
    DIRECTION OUTPUT ;
    USE SIGNAL ;
    ANTENNADIFFAREA 2.724000 ;
    PORT
      LAYER Metal2 ;
        RECT 90.520 0.000 90.920 0.400 ;
    END
  END S1BEG[0]
  PIN S1BEG[1]
    DIRECTION OUTPUT ;
    USE SIGNAL ;
    ANTENNADIFFAREA 2.724000 ;
    PORT
      LAYER Metal2 ;
        RECT 91.480 0.000 91.880 0.400 ;
    END
  END S1BEG[1]
  PIN S1BEG[2]
    DIRECTION OUTPUT ;
    USE SIGNAL ;
    ANTENNADIFFAREA 2.724000 ;
    PORT
      LAYER Metal2 ;
        RECT 92.440 0.000 92.840 0.400 ;
    END
  END S1BEG[2]
  PIN S1BEG[3]
    DIRECTION OUTPUT ;
    USE SIGNAL ;
    ANTENNADIFFAREA 2.724000 ;
    PORT
      LAYER Metal2 ;
        RECT 93.400 0.000 93.800 0.400 ;
    END
  END S1BEG[3]
  PIN S2BEG[0]
    DIRECTION OUTPUT ;
    USE SIGNAL ;
    ANTENNADIFFAREA 2.724000 ;
    PORT
      LAYER Metal2 ;
        RECT 99.160 0.000 99.560 0.400 ;
    END
  END S2BEG[0]
  PIN S2BEG[1]
    DIRECTION OUTPUT ;
    USE SIGNAL ;
    ANTENNADIFFAREA 2.724000 ;
    PORT
      LAYER Metal2 ;
        RECT 100.120 0.000 100.520 0.400 ;
    END
  END S2BEG[1]
  PIN S2BEG[2]
    DIRECTION OUTPUT ;
    USE SIGNAL ;
    ANTENNADIFFAREA 2.724000 ;
    PORT
      LAYER Metal2 ;
        RECT 101.080 0.000 101.480 0.400 ;
    END
  END S2BEG[2]
  PIN S2BEG[3]
    DIRECTION OUTPUT ;
    USE SIGNAL ;
    ANTENNADIFFAREA 2.724000 ;
    PORT
      LAYER Metal2 ;
        RECT 102.040 0.000 102.440 0.400 ;
    END
  END S2BEG[3]
  PIN S2BEG[4]
    DIRECTION OUTPUT ;
    USE SIGNAL ;
    ANTENNADIFFAREA 2.724000 ;
    PORT
      LAYER Metal2 ;
        RECT 103.000 0.000 103.400 0.400 ;
    END
  END S2BEG[4]
  PIN S2BEG[5]
    DIRECTION OUTPUT ;
    USE SIGNAL ;
    ANTENNADIFFAREA 2.724000 ;
    PORT
      LAYER Metal2 ;
        RECT 103.960 0.000 104.360 0.400 ;
    END
  END S2BEG[5]
  PIN S2BEG[6]
    DIRECTION OUTPUT ;
    USE SIGNAL ;
    ANTENNADIFFAREA 2.724000 ;
    PORT
      LAYER Metal2 ;
        RECT 104.920 0.000 105.320 0.400 ;
    END
  END S2BEG[6]
  PIN S2BEG[7]
    DIRECTION OUTPUT ;
    USE SIGNAL ;
    ANTENNADIFFAREA 2.724000 ;
    PORT
      LAYER Metal2 ;
        RECT 105.880 0.000 106.280 0.400 ;
    END
  END S2BEG[7]
  PIN S2BEGb[0]
    DIRECTION OUTPUT ;
    USE SIGNAL ;
    ANTENNADIFFAREA 2.724000 ;
    PORT
      LAYER Metal2 ;
        RECT 113.560 0.000 113.960 0.400 ;
    END
  END S2BEGb[0]
  PIN S2BEGb[1]
    DIRECTION OUTPUT ;
    USE SIGNAL ;
    ANTENNADIFFAREA 2.724000 ;
    PORT
      LAYER Metal2 ;
        RECT 114.520 0.000 114.920 0.400 ;
    END
  END S2BEGb[1]
  PIN S2BEGb[2]
    DIRECTION OUTPUT ;
    USE SIGNAL ;
    ANTENNADIFFAREA 2.724000 ;
    PORT
      LAYER Metal2 ;
        RECT 115.480 0.000 115.880 0.400 ;
    END
  END S2BEGb[2]
  PIN S2BEGb[3]
    DIRECTION OUTPUT ;
    USE SIGNAL ;
    ANTENNADIFFAREA 2.724000 ;
    PORT
      LAYER Metal2 ;
        RECT 116.440 0.000 116.840 0.400 ;
    END
  END S2BEGb[3]
  PIN S2BEGb[4]
    DIRECTION OUTPUT ;
    USE SIGNAL ;
    ANTENNADIFFAREA 2.724000 ;
    PORT
      LAYER Metal2 ;
        RECT 117.400 0.000 117.800 0.400 ;
    END
  END S2BEGb[4]
  PIN S2BEGb[5]
    DIRECTION OUTPUT ;
    USE SIGNAL ;
    ANTENNADIFFAREA 2.724000 ;
    PORT
      LAYER Metal2 ;
        RECT 118.360 0.000 118.760 0.400 ;
    END
  END S2BEGb[5]
  PIN S2BEGb[6]
    DIRECTION OUTPUT ;
    USE SIGNAL ;
    ANTENNADIFFAREA 2.724000 ;
    PORT
      LAYER Metal2 ;
        RECT 119.320 0.000 119.720 0.400 ;
    END
  END S2BEGb[6]
  PIN S2BEGb[7]
    DIRECTION OUTPUT ;
    USE SIGNAL ;
    ANTENNADIFFAREA 2.724000 ;
    PORT
      LAYER Metal2 ;
        RECT 120.280 0.000 120.680 0.400 ;
    END
  END S2BEGb[7]
  PIN S4BEG[0]
    DIRECTION OUTPUT ;
    USE SIGNAL ;
    ANTENNADIFFAREA 2.724000 ;
    PORT
      LAYER Metal2 ;
        RECT 129.880 0.000 130.280 0.400 ;
    END
  END S4BEG[0]
  PIN S4BEG[10]
    DIRECTION OUTPUT ;
    USE SIGNAL ;
    ANTENNADIFFAREA 2.724000 ;
    PORT
      LAYER Metal2 ;
        RECT 139.480 0.000 139.880 0.400 ;
    END
  END S4BEG[10]
  PIN S4BEG[11]
    DIRECTION OUTPUT ;
    USE SIGNAL ;
    ANTENNADIFFAREA 2.724000 ;
    PORT
      LAYER Metal2 ;
        RECT 140.440 0.000 140.840 0.400 ;
    END
  END S4BEG[11]
  PIN S4BEG[12]
    DIRECTION OUTPUT ;
    USE SIGNAL ;
    ANTENNADIFFAREA 2.724000 ;
    PORT
      LAYER Metal2 ;
        RECT 141.400 0.000 141.800 0.400 ;
    END
  END S4BEG[12]
  PIN S4BEG[13]
    DIRECTION OUTPUT ;
    USE SIGNAL ;
    ANTENNADIFFAREA 2.724000 ;
    PORT
      LAYER Metal2 ;
        RECT 142.360 0.000 142.760 0.400 ;
    END
  END S4BEG[13]
  PIN S4BEG[14]
    DIRECTION OUTPUT ;
    USE SIGNAL ;
    ANTENNADIFFAREA 2.724000 ;
    PORT
      LAYER Metal2 ;
        RECT 143.320 0.000 143.720 0.400 ;
    END
  END S4BEG[14]
  PIN S4BEG[15]
    DIRECTION OUTPUT ;
    USE SIGNAL ;
    ANTENNADIFFAREA 2.724000 ;
    PORT
      LAYER Metal2 ;
        RECT 144.280 0.000 144.680 0.400 ;
    END
  END S4BEG[15]
  PIN S4BEG[1]
    DIRECTION OUTPUT ;
    USE SIGNAL ;
    ANTENNADIFFAREA 2.724000 ;
    PORT
      LAYER Metal2 ;
        RECT 130.840 0.000 131.240 0.400 ;
    END
  END S4BEG[1]
  PIN S4BEG[2]
    DIRECTION OUTPUT ;
    USE SIGNAL ;
    ANTENNADIFFAREA 2.724000 ;
    PORT
      LAYER Metal2 ;
        RECT 131.800 0.000 132.200 0.400 ;
    END
  END S4BEG[2]
  PIN S4BEG[3]
    DIRECTION OUTPUT ;
    USE SIGNAL ;
    ANTENNADIFFAREA 2.724000 ;
    PORT
      LAYER Metal2 ;
        RECT 132.760 0.000 133.160 0.400 ;
    END
  END S4BEG[3]
  PIN S4BEG[4]
    DIRECTION OUTPUT ;
    USE SIGNAL ;
    ANTENNADIFFAREA 2.724000 ;
    PORT
      LAYER Metal2 ;
        RECT 133.720 0.000 134.120 0.400 ;
    END
  END S4BEG[4]
  PIN S4BEG[5]
    DIRECTION OUTPUT ;
    USE SIGNAL ;
    ANTENNADIFFAREA 2.724000 ;
    PORT
      LAYER Metal2 ;
        RECT 134.680 0.000 135.080 0.400 ;
    END
  END S4BEG[5]
  PIN S4BEG[6]
    DIRECTION OUTPUT ;
    USE SIGNAL ;
    ANTENNADIFFAREA 2.724000 ;
    PORT
      LAYER Metal2 ;
        RECT 135.640 0.000 136.040 0.400 ;
    END
  END S4BEG[6]
  PIN S4BEG[7]
    DIRECTION OUTPUT ;
    USE SIGNAL ;
    ANTENNADIFFAREA 2.724000 ;
    PORT
      LAYER Metal2 ;
        RECT 136.600 0.000 137.000 0.400 ;
    END
  END S4BEG[7]
  PIN S4BEG[8]
    DIRECTION OUTPUT ;
    USE SIGNAL ;
    ANTENNADIFFAREA 2.724000 ;
    PORT
      LAYER Metal2 ;
        RECT 137.560 0.000 137.960 0.400 ;
    END
  END S4BEG[8]
  PIN S4BEG[9]
    DIRECTION OUTPUT ;
    USE SIGNAL ;
    ANTENNADIFFAREA 2.724000 ;
    PORT
      LAYER Metal2 ;
        RECT 138.520 0.000 138.920 0.400 ;
    END
  END S4BEG[9]
  PIN SS4BEG[0]
    DIRECTION OUTPUT ;
    USE SIGNAL ;
    ANTENNADIFFAREA 2.724000 ;
    PORT
      LAYER Metal2 ;
        RECT 157.720 0.000 158.120 0.400 ;
    END
  END SS4BEG[0]
  PIN SS4BEG[10]
    DIRECTION OUTPUT ;
    USE SIGNAL ;
    ANTENNADIFFAREA 2.724000 ;
    PORT
      LAYER Metal2 ;
        RECT 167.320 0.000 167.720 0.400 ;
    END
  END SS4BEG[10]
  PIN SS4BEG[11]
    DIRECTION OUTPUT ;
    USE SIGNAL ;
    ANTENNADIFFAREA 2.724000 ;
    PORT
      LAYER Metal2 ;
        RECT 168.280 0.000 168.680 0.400 ;
    END
  END SS4BEG[11]
  PIN SS4BEG[12]
    DIRECTION OUTPUT ;
    USE SIGNAL ;
    ANTENNADIFFAREA 2.724000 ;
    PORT
      LAYER Metal2 ;
        RECT 169.240 0.000 169.640 0.400 ;
    END
  END SS4BEG[12]
  PIN SS4BEG[13]
    DIRECTION OUTPUT ;
    USE SIGNAL ;
    ANTENNADIFFAREA 2.724000 ;
    PORT
      LAYER Metal2 ;
        RECT 170.200 0.000 170.600 0.400 ;
    END
  END SS4BEG[13]
  PIN SS4BEG[14]
    DIRECTION OUTPUT ;
    USE SIGNAL ;
    ANTENNADIFFAREA 2.724000 ;
    PORT
      LAYER Metal2 ;
        RECT 171.160 0.000 171.560 0.400 ;
    END
  END SS4BEG[14]
  PIN SS4BEG[15]
    DIRECTION OUTPUT ;
    USE SIGNAL ;
    ANTENNADIFFAREA 2.724000 ;
    PORT
      LAYER Metal2 ;
        RECT 172.120 0.000 172.520 0.400 ;
    END
  END SS4BEG[15]
  PIN SS4BEG[1]
    DIRECTION OUTPUT ;
    USE SIGNAL ;
    ANTENNADIFFAREA 2.724000 ;
    PORT
      LAYER Metal2 ;
        RECT 158.680 0.000 159.080 0.400 ;
    END
  END SS4BEG[1]
  PIN SS4BEG[2]
    DIRECTION OUTPUT ;
    USE SIGNAL ;
    ANTENNADIFFAREA 2.724000 ;
    PORT
      LAYER Metal2 ;
        RECT 159.640 0.000 160.040 0.400 ;
    END
  END SS4BEG[2]
  PIN SS4BEG[3]
    DIRECTION OUTPUT ;
    USE SIGNAL ;
    ANTENNADIFFAREA 2.724000 ;
    PORT
      LAYER Metal2 ;
        RECT 160.600 0.000 161.000 0.400 ;
    END
  END SS4BEG[3]
  PIN SS4BEG[4]
    DIRECTION OUTPUT ;
    USE SIGNAL ;
    ANTENNADIFFAREA 2.724000 ;
    PORT
      LAYER Metal2 ;
        RECT 161.560 0.000 161.960 0.400 ;
    END
  END SS4BEG[4]
  PIN SS4BEG[5]
    DIRECTION OUTPUT ;
    USE SIGNAL ;
    ANTENNADIFFAREA 2.724000 ;
    PORT
      LAYER Metal2 ;
        RECT 162.520 0.000 162.920 0.400 ;
    END
  END SS4BEG[5]
  PIN SS4BEG[6]
    DIRECTION OUTPUT ;
    USE SIGNAL ;
    ANTENNADIFFAREA 2.724000 ;
    PORT
      LAYER Metal2 ;
        RECT 163.480 0.000 163.880 0.400 ;
    END
  END SS4BEG[6]
  PIN SS4BEG[7]
    DIRECTION OUTPUT ;
    USE SIGNAL ;
    ANTENNADIFFAREA 2.724000 ;
    PORT
      LAYER Metal2 ;
        RECT 164.440 0.000 164.840 0.400 ;
    END
  END SS4BEG[7]
  PIN SS4BEG[8]
    DIRECTION OUTPUT ;
    USE SIGNAL ;
    ANTENNADIFFAREA 2.724000 ;
    PORT
      LAYER Metal2 ;
        RECT 165.400 0.000 165.800 0.400 ;
    END
  END SS4BEG[8]
  PIN SS4BEG[9]
    DIRECTION OUTPUT ;
    USE SIGNAL ;
    ANTENNADIFFAREA 2.724000 ;
    PORT
      LAYER Metal2 ;
        RECT 166.360 0.000 166.760 0.400 ;
    END
  END SS4BEG[9]
  PIN UIO_TOP_UIN0
    DIRECTION INPUT ;
    USE SIGNAL ;
    ANTENNAGATEAREA 0.180700 ;
    ANTENNADIFFAREA 2.015400 ;
    PORT
      LAYER Metal2 ;
        RECT 87.640 54.200 88.040 54.600 ;
    END
  END UIO_TOP_UIN0
  PIN UIO_TOP_UIN1
    DIRECTION INPUT ;
    USE SIGNAL ;
    ANTENNAGATEAREA 0.180700 ;
    ANTENNADIFFAREA 2.015400 ;
    PORT
      LAYER Metal2 ;
        RECT 90.520 54.200 90.920 54.600 ;
    END
  END UIO_TOP_UIN1
  PIN UIO_TOP_UIN10
    DIRECTION INPUT ;
    USE SIGNAL ;
    ANTENNAGATEAREA 0.180700 ;
    ANTENNADIFFAREA 2.015400 ;
    PORT
      LAYER Metal2 ;
        RECT 116.440 54.200 116.840 54.600 ;
    END
  END UIO_TOP_UIN10
  PIN UIO_TOP_UIN11
    DIRECTION INPUT ;
    USE SIGNAL ;
    ANTENNAGATEAREA 0.180700 ;
    ANTENNADIFFAREA 2.015400 ;
    PORT
      LAYER Metal2 ;
        RECT 119.320 54.200 119.720 54.600 ;
    END
  END UIO_TOP_UIN11
  PIN UIO_TOP_UIN12
    DIRECTION INPUT ;
    USE SIGNAL ;
    ANTENNAGATEAREA 0.180700 ;
    ANTENNADIFFAREA 2.015400 ;
    PORT
      LAYER Metal2 ;
        RECT 122.200 54.200 122.600 54.600 ;
    END
  END UIO_TOP_UIN12
  PIN UIO_TOP_UIN13
    DIRECTION INPUT ;
    USE SIGNAL ;
    ANTENNAGATEAREA 0.180700 ;
    ANTENNADIFFAREA 2.015400 ;
    PORT
      LAYER Metal2 ;
        RECT 125.080 54.200 125.480 54.600 ;
    END
  END UIO_TOP_UIN13
  PIN UIO_TOP_UIN14
    DIRECTION INPUT ;
    USE SIGNAL ;
    ANTENNAGATEAREA 0.180700 ;
    ANTENNADIFFAREA 2.015400 ;
    PORT
      LAYER Metal2 ;
        RECT 127.960 54.200 128.360 54.600 ;
    END
  END UIO_TOP_UIN14
  PIN UIO_TOP_UIN15
    DIRECTION INPUT ;
    USE SIGNAL ;
    ANTENNAGATEAREA 0.180700 ;
    ANTENNADIFFAREA 2.015400 ;
    PORT
      LAYER Metal2 ;
        RECT 130.840 54.200 131.240 54.600 ;
    END
  END UIO_TOP_UIN15
  PIN UIO_TOP_UIN16
    DIRECTION INPUT ;
    USE SIGNAL ;
    ANTENNAGATEAREA 0.180700 ;
    ANTENNADIFFAREA 2.015400 ;
    PORT
      LAYER Metal2 ;
        RECT 133.720 54.200 134.120 54.600 ;
    END
  END UIO_TOP_UIN16
  PIN UIO_TOP_UIN17
    DIRECTION INPUT ;
    USE SIGNAL ;
    ANTENNAGATEAREA 0.180700 ;
    ANTENNADIFFAREA 2.015400 ;
    PORT
      LAYER Metal2 ;
        RECT 136.600 54.200 137.000 54.600 ;
    END
  END UIO_TOP_UIN17
  PIN UIO_TOP_UIN18
    DIRECTION INPUT ;
    USE SIGNAL ;
    ANTENNAGATEAREA 0.180700 ;
    ANTENNADIFFAREA 2.015400 ;
    PORT
      LAYER Metal2 ;
        RECT 139.480 54.200 139.880 54.600 ;
    END
  END UIO_TOP_UIN18
  PIN UIO_TOP_UIN19
    DIRECTION INPUT ;
    USE SIGNAL ;
    ANTENNAGATEAREA 0.180700 ;
    ANTENNADIFFAREA 2.015400 ;
    PORT
      LAYER Metal2 ;
        RECT 142.360 54.200 142.760 54.600 ;
    END
  END UIO_TOP_UIN19
  PIN UIO_TOP_UIN2
    DIRECTION INPUT ;
    USE SIGNAL ;
    ANTENNAGATEAREA 0.180700 ;
    ANTENNADIFFAREA 2.015400 ;
    PORT
      LAYER Metal2 ;
        RECT 93.400 54.200 93.800 54.600 ;
    END
  END UIO_TOP_UIN2
  PIN UIO_TOP_UIN3
    DIRECTION INPUT ;
    USE SIGNAL ;
    ANTENNAGATEAREA 0.180700 ;
    ANTENNADIFFAREA 2.015400 ;
    PORT
      LAYER Metal2 ;
        RECT 96.280 54.200 96.680 54.600 ;
    END
  END UIO_TOP_UIN3
  PIN UIO_TOP_UIN4
    DIRECTION INPUT ;
    USE SIGNAL ;
    ANTENNAGATEAREA 0.180700 ;
    ANTENNADIFFAREA 2.015400 ;
    PORT
      LAYER Metal2 ;
        RECT 99.160 54.200 99.560 54.600 ;
    END
  END UIO_TOP_UIN4
  PIN UIO_TOP_UIN5
    DIRECTION INPUT ;
    USE SIGNAL ;
    ANTENNAGATEAREA 0.180700 ;
    ANTENNADIFFAREA 2.015400 ;
    PORT
      LAYER Metal2 ;
        RECT 102.040 54.200 102.440 54.600 ;
    END
  END UIO_TOP_UIN5
  PIN UIO_TOP_UIN6
    DIRECTION INPUT ;
    USE SIGNAL ;
    ANTENNAGATEAREA 0.180700 ;
    ANTENNADIFFAREA 2.015400 ;
    PORT
      LAYER Metal2 ;
        RECT 104.920 54.200 105.320 54.600 ;
    END
  END UIO_TOP_UIN6
  PIN UIO_TOP_UIN7
    DIRECTION INPUT ;
    USE SIGNAL ;
    ANTENNAGATEAREA 0.180700 ;
    ANTENNADIFFAREA 2.015400 ;
    PORT
      LAYER Metal2 ;
        RECT 107.800 54.200 108.200 54.600 ;
    END
  END UIO_TOP_UIN7
  PIN UIO_TOP_UIN8
    DIRECTION INPUT ;
    USE SIGNAL ;
    ANTENNAGATEAREA 0.180700 ;
    ANTENNADIFFAREA 2.015400 ;
    PORT
      LAYER Metal2 ;
        RECT 110.680 54.200 111.080 54.600 ;
    END
  END UIO_TOP_UIN8
  PIN UIO_TOP_UIN9
    DIRECTION INPUT ;
    USE SIGNAL ;
    ANTENNAGATEAREA 0.180700 ;
    ANTENNADIFFAREA 2.015400 ;
    PORT
      LAYER Metal2 ;
        RECT 113.560 54.200 113.960 54.600 ;
    END
  END UIO_TOP_UIN9
  PIN UIO_TOP_UOUT0
    DIRECTION OUTPUT ;
    USE SIGNAL ;
    ANTENNADIFFAREA 2.724000 ;
    PORT
      LAYER Metal2 ;
        RECT 145.240 54.200 145.640 54.600 ;
    END
  END UIO_TOP_UOUT0
  PIN UIO_TOP_UOUT1
    DIRECTION OUTPUT ;
    USE SIGNAL ;
    ANTENNADIFFAREA 2.724000 ;
    PORT
      LAYER Metal2 ;
        RECT 148.120 54.200 148.520 54.600 ;
    END
  END UIO_TOP_UOUT1
  PIN UIO_TOP_UOUT10
    DIRECTION OUTPUT ;
    USE SIGNAL ;
    ANTENNADIFFAREA 2.724000 ;
    PORT
      LAYER Metal2 ;
        RECT 174.040 54.200 174.440 54.600 ;
    END
  END UIO_TOP_UOUT10
  PIN UIO_TOP_UOUT11
    DIRECTION OUTPUT ;
    USE SIGNAL ;
    ANTENNADIFFAREA 2.724000 ;
    PORT
      LAYER Metal2 ;
        RECT 176.920 54.200 177.320 54.600 ;
    END
  END UIO_TOP_UOUT11
  PIN UIO_TOP_UOUT12
    DIRECTION OUTPUT ;
    USE SIGNAL ;
    ANTENNADIFFAREA 2.724000 ;
    PORT
      LAYER Metal2 ;
        RECT 179.800 54.200 180.200 54.600 ;
    END
  END UIO_TOP_UOUT12
  PIN UIO_TOP_UOUT13
    DIRECTION OUTPUT ;
    USE SIGNAL ;
    ANTENNADIFFAREA 2.724000 ;
    PORT
      LAYER Metal2 ;
        RECT 182.680 54.200 183.080 54.600 ;
    END
  END UIO_TOP_UOUT13
  PIN UIO_TOP_UOUT14
    DIRECTION OUTPUT ;
    USE SIGNAL ;
    ANTENNADIFFAREA 2.724000 ;
    PORT
      LAYER Metal2 ;
        RECT 185.560 54.200 185.960 54.600 ;
    END
  END UIO_TOP_UOUT14
  PIN UIO_TOP_UOUT15
    DIRECTION OUTPUT ;
    USE SIGNAL ;
    ANTENNADIFFAREA 2.724000 ;
    PORT
      LAYER Metal2 ;
        RECT 188.440 54.200 188.840 54.600 ;
    END
  END UIO_TOP_UOUT15
  PIN UIO_TOP_UOUT16
    DIRECTION OUTPUT ;
    USE SIGNAL ;
    ANTENNADIFFAREA 2.724000 ;
    PORT
      LAYER Metal2 ;
        RECT 191.320 54.200 191.720 54.600 ;
    END
  END UIO_TOP_UOUT16
  PIN UIO_TOP_UOUT17
    DIRECTION OUTPUT ;
    USE SIGNAL ;
    ANTENNADIFFAREA 2.724000 ;
    PORT
      LAYER Metal2 ;
        RECT 194.200 54.200 194.600 54.600 ;
    END
  END UIO_TOP_UOUT17
  PIN UIO_TOP_UOUT18
    DIRECTION OUTPUT ;
    USE SIGNAL ;
    ANTENNADIFFAREA 2.724000 ;
    PORT
      LAYER Metal2 ;
        RECT 197.080 54.200 197.480 54.600 ;
    END
  END UIO_TOP_UOUT18
  PIN UIO_TOP_UOUT19
    DIRECTION OUTPUT ;
    USE SIGNAL ;
    ANTENNADIFFAREA 2.724000 ;
    PORT
      LAYER Metal2 ;
        RECT 199.960 54.200 200.360 54.600 ;
    END
  END UIO_TOP_UOUT19
  PIN UIO_TOP_UOUT2
    DIRECTION OUTPUT ;
    USE SIGNAL ;
    ANTENNADIFFAREA 2.724000 ;
    PORT
      LAYER Metal2 ;
        RECT 151.000 54.200 151.400 54.600 ;
    END
  END UIO_TOP_UOUT2
  PIN UIO_TOP_UOUT3
    DIRECTION OUTPUT ;
    USE SIGNAL ;
    ANTENNADIFFAREA 2.724000 ;
    PORT
      LAYER Metal2 ;
        RECT 153.880 54.200 154.280 54.600 ;
    END
  END UIO_TOP_UOUT3
  PIN UIO_TOP_UOUT4
    DIRECTION OUTPUT ;
    USE SIGNAL ;
    ANTENNADIFFAREA 2.724000 ;
    PORT
      LAYER Metal2 ;
        RECT 156.760 54.200 157.160 54.600 ;
    END
  END UIO_TOP_UOUT4
  PIN UIO_TOP_UOUT5
    DIRECTION OUTPUT ;
    USE SIGNAL ;
    ANTENNADIFFAREA 2.724000 ;
    PORT
      LAYER Metal2 ;
        RECT 159.640 54.200 160.040 54.600 ;
    END
  END UIO_TOP_UOUT5
  PIN UIO_TOP_UOUT6
    DIRECTION OUTPUT ;
    USE SIGNAL ;
    ANTENNADIFFAREA 2.724000 ;
    PORT
      LAYER Metal2 ;
        RECT 162.520 54.200 162.920 54.600 ;
    END
  END UIO_TOP_UOUT6
  PIN UIO_TOP_UOUT7
    DIRECTION OUTPUT ;
    USE SIGNAL ;
    ANTENNADIFFAREA 2.724000 ;
    PORT
      LAYER Metal2 ;
        RECT 165.400 54.200 165.800 54.600 ;
    END
  END UIO_TOP_UOUT7
  PIN UIO_TOP_UOUT8
    DIRECTION OUTPUT ;
    USE SIGNAL ;
    ANTENNADIFFAREA 2.724000 ;
    PORT
      LAYER Metal2 ;
        RECT 168.280 54.200 168.680 54.600 ;
    END
  END UIO_TOP_UOUT8
  PIN UIO_TOP_UOUT9
    DIRECTION OUTPUT ;
    USE SIGNAL ;
    ANTENNADIFFAREA 2.724000 ;
    PORT
      LAYER Metal2 ;
        RECT 171.160 54.200 171.560 54.600 ;
    END
  END UIO_TOP_UOUT9
  PIN UserCLK
    DIRECTION INPUT ;
    USE SIGNAL ;
    ANTENNAGATEAREA 0.725400 ;
    PORT
      LAYER Metal3 ;
        RECT 0.000 1.060 0.400 1.460 ;
    END
  END UserCLK
  PIN UserCLKo
    DIRECTION OUTPUT ;
    USE SIGNAL ;
    ANTENNADIFFAREA 2.724000 ;
    PORT
      LAYER Metal3 ;
        RECT 215.600 1.060 216.000 1.460 ;
    END
  END UserCLKo
  PIN VGND
    DIRECTION INOUT ;
    USE GROUND ;
    PORT
      LAYER Metal4 ;
        RECT 21.580 0.000 23.780 54.600 ;
    END
    PORT
      LAYER Metal4 ;
        RECT 97.180 0.000 99.380 54.600 ;
    END
    PORT
      LAYER Metal4 ;
        RECT 172.780 0.000 174.980 54.600 ;
    END
  END VGND
  PIN VPWR
    DIRECTION INOUT ;
    USE POWER ;
    PORT
      LAYER Metal4 ;
        RECT 15.380 0.000 17.580 54.600 ;
    END
    PORT
      LAYER Metal4 ;
        RECT 90.980 0.000 93.180 54.600 ;
    END
    PORT
      LAYER Metal4 ;
        RECT 166.580 0.000 168.780 54.600 ;
    END
  END VPWR
  OBS
      LAYER GatPoly ;
        RECT 2.880 3.630 213.120 49.290 ;
      LAYER Metal1 ;
        RECT 2.880 3.560 213.120 49.360 ;
      LAYER Metal2 ;
        RECT 0.375 53.990 8.710 54.325 ;
        RECT 9.530 53.990 11.590 54.325 ;
        RECT 12.410 53.990 14.470 54.325 ;
        RECT 15.290 53.990 17.350 54.325 ;
        RECT 18.170 53.990 20.230 54.325 ;
        RECT 21.050 53.990 23.110 54.325 ;
        RECT 23.930 53.990 25.990 54.325 ;
        RECT 26.810 53.990 28.870 54.325 ;
        RECT 29.690 53.990 31.750 54.325 ;
        RECT 32.570 53.990 34.630 54.325 ;
        RECT 35.450 53.990 37.510 54.325 ;
        RECT 38.330 53.990 40.390 54.325 ;
        RECT 41.210 53.990 43.270 54.325 ;
        RECT 44.090 53.990 46.150 54.325 ;
        RECT 46.970 53.990 49.030 54.325 ;
        RECT 49.850 53.990 51.910 54.325 ;
        RECT 52.730 53.990 54.790 54.325 ;
        RECT 55.610 53.990 57.670 54.325 ;
        RECT 58.490 53.990 60.550 54.325 ;
        RECT 61.370 53.990 63.430 54.325 ;
        RECT 64.250 53.990 87.430 54.325 ;
        RECT 88.250 53.990 90.310 54.325 ;
        RECT 91.130 53.990 93.190 54.325 ;
        RECT 94.010 53.990 96.070 54.325 ;
        RECT 96.890 53.990 98.950 54.325 ;
        RECT 99.770 53.990 101.830 54.325 ;
        RECT 102.650 53.990 104.710 54.325 ;
        RECT 105.530 53.990 107.590 54.325 ;
        RECT 108.410 53.990 110.470 54.325 ;
        RECT 111.290 53.990 113.350 54.325 ;
        RECT 114.170 53.990 116.230 54.325 ;
        RECT 117.050 53.990 119.110 54.325 ;
        RECT 119.930 53.990 121.990 54.325 ;
        RECT 122.810 53.990 124.870 54.325 ;
        RECT 125.690 53.990 127.750 54.325 ;
        RECT 128.570 53.990 130.630 54.325 ;
        RECT 131.450 53.990 133.510 54.325 ;
        RECT 134.330 53.990 136.390 54.325 ;
        RECT 137.210 53.990 139.270 54.325 ;
        RECT 140.090 53.990 142.150 54.325 ;
        RECT 142.970 53.990 145.030 54.325 ;
        RECT 145.850 53.990 147.910 54.325 ;
        RECT 148.730 53.990 150.790 54.325 ;
        RECT 151.610 53.990 153.670 54.325 ;
        RECT 154.490 53.990 156.550 54.325 ;
        RECT 157.370 53.990 159.430 54.325 ;
        RECT 160.250 53.990 162.310 54.325 ;
        RECT 163.130 53.990 165.190 54.325 ;
        RECT 166.010 53.990 168.070 54.325 ;
        RECT 168.890 53.990 170.950 54.325 ;
        RECT 171.770 53.990 173.830 54.325 ;
        RECT 174.650 53.990 176.710 54.325 ;
        RECT 177.530 53.990 179.590 54.325 ;
        RECT 180.410 53.990 182.470 54.325 ;
        RECT 183.290 53.990 185.350 54.325 ;
        RECT 186.170 53.990 188.230 54.325 ;
        RECT 189.050 53.990 191.110 54.325 ;
        RECT 191.930 53.990 193.990 54.325 ;
        RECT 194.810 53.990 196.870 54.325 ;
        RECT 197.690 53.990 199.750 54.325 ;
        RECT 200.570 53.990 215.625 54.325 ;
        RECT 0.375 0.610 215.625 53.990 ;
        RECT 0.375 0.275 1.990 0.610 ;
        RECT 2.810 0.275 2.950 0.610 ;
        RECT 3.770 0.275 3.910 0.610 ;
        RECT 4.730 0.275 4.870 0.610 ;
        RECT 5.690 0.275 10.630 0.610 ;
        RECT 11.450 0.275 11.590 0.610 ;
        RECT 12.410 0.275 12.550 0.610 ;
        RECT 13.370 0.275 13.510 0.610 ;
        RECT 14.330 0.275 14.470 0.610 ;
        RECT 15.290 0.275 15.430 0.610 ;
        RECT 16.250 0.275 16.390 0.610 ;
        RECT 17.210 0.275 17.350 0.610 ;
        RECT 18.170 0.275 24.070 0.610 ;
        RECT 24.890 0.275 25.030 0.610 ;
        RECT 25.850 0.275 25.990 0.610 ;
        RECT 26.810 0.275 26.950 0.610 ;
        RECT 27.770 0.275 27.910 0.610 ;
        RECT 28.730 0.275 28.870 0.610 ;
        RECT 29.690 0.275 29.830 0.610 ;
        RECT 30.650 0.275 30.790 0.610 ;
        RECT 31.610 0.275 40.390 0.610 ;
        RECT 41.210 0.275 41.350 0.610 ;
        RECT 42.170 0.275 42.310 0.610 ;
        RECT 43.130 0.275 43.270 0.610 ;
        RECT 44.090 0.275 44.230 0.610 ;
        RECT 45.050 0.275 45.190 0.610 ;
        RECT 46.010 0.275 46.150 0.610 ;
        RECT 46.970 0.275 47.110 0.610 ;
        RECT 47.930 0.275 48.070 0.610 ;
        RECT 48.890 0.275 49.030 0.610 ;
        RECT 49.850 0.275 49.990 0.610 ;
        RECT 50.810 0.275 50.950 0.610 ;
        RECT 51.770 0.275 51.910 0.610 ;
        RECT 52.730 0.275 52.870 0.610 ;
        RECT 53.690 0.275 53.830 0.610 ;
        RECT 54.650 0.275 54.790 0.610 ;
        RECT 55.610 0.275 68.230 0.610 ;
        RECT 69.050 0.275 69.190 0.610 ;
        RECT 70.010 0.275 70.150 0.610 ;
        RECT 70.970 0.275 71.110 0.610 ;
        RECT 71.930 0.275 72.070 0.610 ;
        RECT 72.890 0.275 73.030 0.610 ;
        RECT 73.850 0.275 73.990 0.610 ;
        RECT 74.810 0.275 74.950 0.610 ;
        RECT 75.770 0.275 75.910 0.610 ;
        RECT 76.730 0.275 76.870 0.610 ;
        RECT 77.690 0.275 77.830 0.610 ;
        RECT 78.650 0.275 78.790 0.610 ;
        RECT 79.610 0.275 79.750 0.610 ;
        RECT 80.570 0.275 80.710 0.610 ;
        RECT 81.530 0.275 81.670 0.610 ;
        RECT 82.490 0.275 82.630 0.610 ;
        RECT 83.450 0.275 90.310 0.610 ;
        RECT 91.130 0.275 91.270 0.610 ;
        RECT 92.090 0.275 92.230 0.610 ;
        RECT 93.050 0.275 93.190 0.610 ;
        RECT 94.010 0.275 98.950 0.610 ;
        RECT 99.770 0.275 99.910 0.610 ;
        RECT 100.730 0.275 100.870 0.610 ;
        RECT 101.690 0.275 101.830 0.610 ;
        RECT 102.650 0.275 102.790 0.610 ;
        RECT 103.610 0.275 103.750 0.610 ;
        RECT 104.570 0.275 104.710 0.610 ;
        RECT 105.530 0.275 105.670 0.610 ;
        RECT 106.490 0.275 113.350 0.610 ;
        RECT 114.170 0.275 114.310 0.610 ;
        RECT 115.130 0.275 115.270 0.610 ;
        RECT 116.090 0.275 116.230 0.610 ;
        RECT 117.050 0.275 117.190 0.610 ;
        RECT 118.010 0.275 118.150 0.610 ;
        RECT 118.970 0.275 119.110 0.610 ;
        RECT 119.930 0.275 120.070 0.610 ;
        RECT 120.890 0.275 129.670 0.610 ;
        RECT 130.490 0.275 130.630 0.610 ;
        RECT 131.450 0.275 131.590 0.610 ;
        RECT 132.410 0.275 132.550 0.610 ;
        RECT 133.370 0.275 133.510 0.610 ;
        RECT 134.330 0.275 134.470 0.610 ;
        RECT 135.290 0.275 135.430 0.610 ;
        RECT 136.250 0.275 136.390 0.610 ;
        RECT 137.210 0.275 137.350 0.610 ;
        RECT 138.170 0.275 138.310 0.610 ;
        RECT 139.130 0.275 139.270 0.610 ;
        RECT 140.090 0.275 140.230 0.610 ;
        RECT 141.050 0.275 141.190 0.610 ;
        RECT 142.010 0.275 142.150 0.610 ;
        RECT 142.970 0.275 143.110 0.610 ;
        RECT 143.930 0.275 144.070 0.610 ;
        RECT 144.890 0.275 157.510 0.610 ;
        RECT 158.330 0.275 158.470 0.610 ;
        RECT 159.290 0.275 159.430 0.610 ;
        RECT 160.250 0.275 160.390 0.610 ;
        RECT 161.210 0.275 161.350 0.610 ;
        RECT 162.170 0.275 162.310 0.610 ;
        RECT 163.130 0.275 163.270 0.610 ;
        RECT 164.090 0.275 164.230 0.610 ;
        RECT 165.050 0.275 165.190 0.610 ;
        RECT 166.010 0.275 166.150 0.610 ;
        RECT 166.970 0.275 167.110 0.610 ;
        RECT 167.930 0.275 168.070 0.610 ;
        RECT 168.890 0.275 169.030 0.610 ;
        RECT 169.850 0.275 169.990 0.610 ;
        RECT 170.810 0.275 170.950 0.610 ;
        RECT 171.770 0.275 171.910 0.610 ;
        RECT 172.730 0.275 179.590 0.610 ;
        RECT 180.410 0.275 189.190 0.610 ;
        RECT 190.010 0.275 190.150 0.610 ;
        RECT 190.970 0.275 191.110 0.610 ;
        RECT 191.930 0.275 192.070 0.610 ;
        RECT 192.890 0.275 193.030 0.610 ;
        RECT 193.850 0.275 193.990 0.610 ;
        RECT 194.810 0.275 194.950 0.610 ;
        RECT 195.770 0.275 195.910 0.610 ;
        RECT 196.730 0.275 196.870 0.610 ;
        RECT 197.690 0.275 197.830 0.610 ;
        RECT 198.650 0.275 198.790 0.610 ;
        RECT 199.610 0.275 199.750 0.610 ;
        RECT 200.570 0.275 200.710 0.610 ;
        RECT 201.530 0.275 201.670 0.610 ;
        RECT 202.490 0.275 202.630 0.610 ;
        RECT 203.450 0.275 203.590 0.610 ;
        RECT 204.410 0.275 204.550 0.610 ;
        RECT 205.370 0.275 205.510 0.610 ;
        RECT 206.330 0.275 206.470 0.610 ;
        RECT 207.290 0.275 207.430 0.610 ;
        RECT 208.250 0.275 215.625 0.610 ;
      LAYER Metal3 ;
        RECT 0.335 41.990 215.665 54.285 ;
        RECT 0.610 41.170 215.390 41.990 ;
        RECT 0.335 41.150 215.665 41.170 ;
        RECT 0.610 40.330 215.390 41.150 ;
        RECT 0.335 40.310 215.665 40.330 ;
        RECT 0.610 39.490 215.390 40.310 ;
        RECT 0.335 39.470 215.665 39.490 ;
        RECT 0.610 38.650 215.390 39.470 ;
        RECT 0.335 38.630 215.665 38.650 ;
        RECT 0.610 37.810 215.390 38.630 ;
        RECT 0.335 37.790 215.665 37.810 ;
        RECT 0.610 36.970 215.390 37.790 ;
        RECT 0.335 36.950 215.665 36.970 ;
        RECT 0.610 36.130 215.390 36.950 ;
        RECT 0.335 36.110 215.665 36.130 ;
        RECT 0.610 35.290 215.390 36.110 ;
        RECT 0.335 35.270 215.665 35.290 ;
        RECT 0.610 34.450 215.390 35.270 ;
        RECT 0.335 34.430 215.665 34.450 ;
        RECT 0.610 33.610 215.390 34.430 ;
        RECT 0.335 33.590 215.665 33.610 ;
        RECT 0.610 32.770 215.390 33.590 ;
        RECT 0.335 32.750 215.665 32.770 ;
        RECT 0.610 31.930 215.390 32.750 ;
        RECT 0.335 31.910 215.665 31.930 ;
        RECT 0.610 31.090 215.390 31.910 ;
        RECT 0.335 31.070 215.665 31.090 ;
        RECT 0.610 30.250 215.390 31.070 ;
        RECT 0.335 30.230 215.665 30.250 ;
        RECT 0.610 29.410 215.390 30.230 ;
        RECT 0.335 29.390 215.665 29.410 ;
        RECT 0.610 28.570 215.390 29.390 ;
        RECT 0.335 28.550 215.665 28.570 ;
        RECT 0.610 27.730 215.390 28.550 ;
        RECT 0.335 27.710 215.665 27.730 ;
        RECT 0.610 26.890 215.390 27.710 ;
        RECT 0.335 26.870 215.665 26.890 ;
        RECT 0.610 26.050 215.390 26.870 ;
        RECT 0.335 26.030 215.665 26.050 ;
        RECT 0.610 25.210 215.390 26.030 ;
        RECT 0.335 25.190 215.665 25.210 ;
        RECT 0.610 24.370 215.390 25.190 ;
        RECT 0.335 24.350 215.665 24.370 ;
        RECT 0.610 23.530 215.390 24.350 ;
        RECT 0.335 23.510 215.665 23.530 ;
        RECT 0.610 22.690 215.390 23.510 ;
        RECT 0.335 22.670 215.665 22.690 ;
        RECT 0.610 21.850 215.390 22.670 ;
        RECT 0.335 21.830 215.665 21.850 ;
        RECT 0.610 21.010 215.390 21.830 ;
        RECT 0.335 20.990 215.665 21.010 ;
        RECT 0.610 20.170 215.390 20.990 ;
        RECT 0.335 20.150 215.665 20.170 ;
        RECT 0.610 19.330 215.390 20.150 ;
        RECT 0.335 19.310 215.665 19.330 ;
        RECT 0.610 18.490 215.390 19.310 ;
        RECT 0.335 18.470 215.665 18.490 ;
        RECT 0.610 17.650 215.390 18.470 ;
        RECT 0.335 17.630 215.665 17.650 ;
        RECT 0.610 16.810 215.390 17.630 ;
        RECT 0.335 16.790 215.665 16.810 ;
        RECT 0.610 15.970 215.390 16.790 ;
        RECT 0.335 15.950 215.665 15.970 ;
        RECT 0.610 15.130 215.390 15.950 ;
        RECT 0.335 1.670 215.665 15.130 ;
        RECT 0.610 0.850 215.390 1.670 ;
        RECT 0.335 0.320 215.665 0.850 ;
      LAYER Metal4 ;
        RECT 24.170 1.535 90.770 54.325 ;
        RECT 93.390 1.535 96.970 54.325 ;
        RECT 99.590 1.535 166.370 54.325 ;
        RECT 168.990 1.535 172.570 54.325 ;
        RECT 175.190 1.535 212.470 54.325 ;
      LAYER TopMetal1 ;
        RECT 23.660 5.380 212.980 50.340 ;
  END
END N_IO
END LIBRARY

